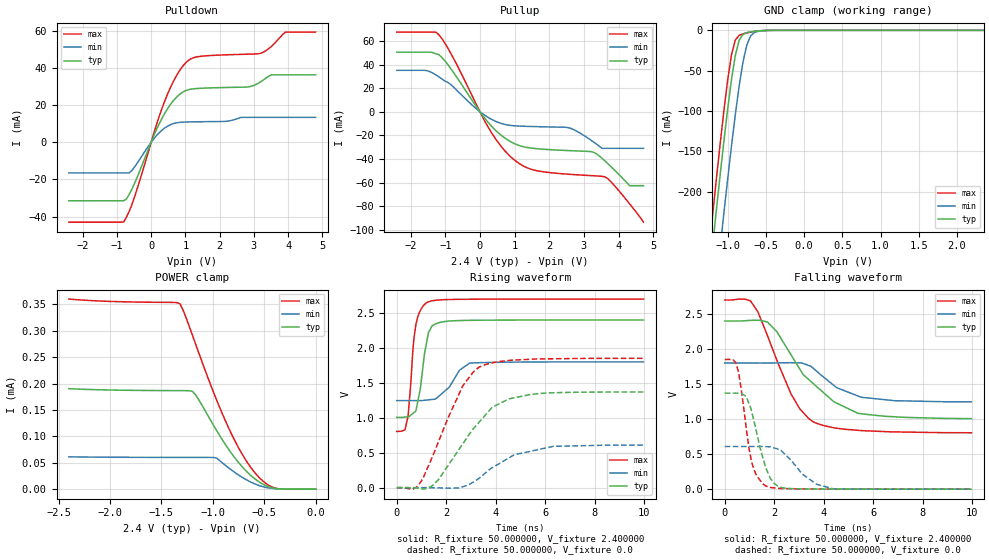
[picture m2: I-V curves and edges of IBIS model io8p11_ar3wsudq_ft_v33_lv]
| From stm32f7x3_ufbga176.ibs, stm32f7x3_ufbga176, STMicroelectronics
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|   Model io8p11_ar3wsudq_ft_v33_lv
[Model]  io8p11_ar3wsudq_ft_v33_lv
Model_type I/O
Polarity   Non-Inverting
Enable   Active-Low
Vinl =   0.720000V
Vinh =   1.680000V
Vmeas =  1.200000V
Cref =   30.000000pF
Rref =   100.000000M
Vref =   0.0V
C_comp   3.742400pF   3.690400pF   3.817400pF
[Temperature Range]   25.000000   0.125000k   -40.000000
[Pullup Reference]   2.400000V   1.800000V   2.700000V
[Pulldown Reference]   0.0V   0.0V   0.0V
[POWER Clamp Reference]   2.400000V   1.800000V   2.700000V
[GND Clamp Reference]   0.0V   0.0V   0.0V
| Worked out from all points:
|   slope of the pulldown table from 0 to 0.36 V, typ, clamps not added: 25 ohm
|   slope of the pullup table from 0 to 0.36 V, typ, clamps not added: 27.7 ohm
|   GND clamp passes 1 mA (typ) near -0.62 V on its own axis
|   rising waveform, R_fixture 50.000000, V_fixture 2.400000: 20-80 % time 350ps typ, 711ps min, 273ps max; typ from 1.01 V to 2.4 V
|   rising waveform, R_fixture 50.000000, V_fixture 0.0: 20-80 % time 1.73ns typ, 1.69ns min, 1.37ns max; typ from 0 V to 1.37 V
|   falling waveform, R_fixture 50.000000, V_fixture 2.400000: 20-80 % time 1.96ns typ, 1.49ns min, 1.39ns max; typ from 2.4 V to 1.01 V
|   falling waveform, R_fixture 50.000000, V_fixture 0.0: 20-80 % time 599ps typ, 1.04ns min, 461ps max; typ from 1.37 V to 0 V
[Pulldown]
|Voltage   I(typ)   I(min)   I(max)
-2.4V     -31.47mA   -16.45mA   -43.01mA
-800mV    -31.47mA   -16.45mA   -42.85mA
-480mV    -21.98mA   -13.17mA   -29.21mA
80mV      3.63mA     1.966mA    5.014mA
480mV     18.16mA    8.738mA    26.02mA
800mV     25.38mA    10.72mA    37.77mA
1.12V     28.53mA    11.02mA    44.6mA
2.8V      29.84mA    13.49mA    47.53mA
3.2V      32.65mA    13.49mA    48.04mA
3.52V     36.4mA     13.49mA    51.83mA
3.92V     36.4mA     13.49mA    59.44mA
4.8V      36.4mA     13.49mA    59.44mA
[Pullup]
|Voltage   I(typ)   I(min)   I(max)
-2.4V     50.45mA    35.09mA    67.46mA
-1.52V    50.45mA    34.74mA    67.46mA
-1.2V     48.61mA    29.87mA    65.61mA
-800mV    34.81mA    21.95mA    47.28mA
320mV     -11.75mA   -6.207mA   -17.08mA
1.04V     -27.54mA   -11.97mA   -41.91mA
1.6V      -31.14mA   -12.58mA   -49.63mA
2.56V     -32.88mA   -13.52mA   -52.9mA
3.28V     -34.25mA   -25.62mA   -54.18mA
3.6V      -41.44mA   -30.96mA   -55.03mA
4.32V     -62.58mA   -30.96mA   -77.98mA
4.72V     -62.58mA   -30.96mA   -93.5mA
[GND_clamp]
|Voltage   I(typ)   I(min)   I(max)
-2.4V     -1.437A    -1.518A    -1.41A
-1.25V    -315.9mA   -407.2mA   -278.2mA
-1.2V     -270.1mA   -361.3mA   -232.1mA
-1.15V    -225mA     -316mA     -186.8mA
-1.1V     -180.9mA   -271.3mA   -142.7mA
-1.05V    -138.2mA   -227.5mA   -100.5mA
-950mV    -61.14mA   -143.6mA   -30.43mA
-900mV    -31.23mA   -104.7mA   -12.14mA
-850mV    -12.49mA   -69.4mA    -6.221mA
-750mV    -2.898mA   -18.35mA   -3.18mA
-600mV    -750.2uA   -1.218mA   -738.3uA
2.35V     0A         0A         0A
[POWER_clamp]
|Voltage   I(typ)   I(min)   I(max)
-2.4V     190.2uA    61.19uA    359.9uA
-1.32V    186.6uA    60.14uA    351.2uA
-1.29V    186.5uA    60.13uA    339.6uA
-1.2V     185.4uA    60.11uA    292.6uA
-1.17V    179.2uA    60.11uA    276.3uA
-960mV    110.2uA    58.62uA    167.5uA
-870mV    82.44uA    43.99uA    126.3uA
-750mV    50.58uA    26.92uA    78.64uA
-630mV    25.94uA    13.41uA    41.02uA
-510mV    9.22uA     4.527uA    14.97uA
-420mV    2.425uA    1.38uA     3.75uA
0V        0A         0A         0A
[Ramp]
| variable   typ   min   max
dV/dt_r  0.82164/1.72879n   0.36981/1.76846n   1.11132/1.36626n
dV/dt_f  0.83208/1.95881n   0.33222/1.49500n   1.13594/1.38984n
R_load = 50.000000
[Rising Waveform]
R_fixture= 50.000000
V_fixture= 2.400000
V_fixture_min= 1.800000
V_fixture_max= 2.700000
|time   V(typ)   V(min)   V(max)
0s        1.006V     1.247V     804.9mV
320.3ps   1.01V      1.247V     824.5mV
460.5ps   1.016V     1.247V     1.037V
660.7ps   1.065V     1.247V     2.01V
760.8ps   1.094V     1.247V     2.307V
961ps     1.44V      1.246V     2.541V
1.221ns   2.109V     1.255V     2.65V
1.562ns   2.343V     1.268V     2.682V
2.943ns   2.395V     1.783V     2.697V
9.97ns    2.4V       1.8V       2.7V
[Rising Waveform]
R_fixture= 50.000000
V_fixture= 0.0
V_fixture_min= 0.0
V_fixture_max= 0.0
|time   V(typ)   V(min)   V(max)
0s        77.96uV    35.29uV    223.3uV
860.9ps   -10.31mV   60.71uV    27.03mV
1.261ns   -5.238mV   -407.8uV   297.9mV
1.682ns   113.2mV    -2.538mV   655mV
2.663ns   624.7mV    12.35mV    1.454V
3.323ns   935.8mV    133.7mV    1.725V
3.864ns   1.151V     286.5mV    1.788V
5.405ns   1.334V     521mV      1.838V
6.326ns   1.358V     591.7mV    1.845V
9.97ns    1.37V      609.1mV    1.851V
[Falling Waveform]
R_fixture= 50.000000
V_fixture= 2.400000
V_fixture_min= 1.800000
V_fixture_max= 2.700000
|time   V(typ)   V(min)   V(max)
0s        2.4V       1.8V       2.7V
1.041ns   2.409V     1.8V       2.687V
1.321ns   2.41V      1.8V       2.544V
1.722ns   2.387V     1.8V       2.197V
2.683ns   1.916V     1.805V     1.358V
3.183ns   1.63V      1.792V     1.089V
3.604ns   1.499V     1.718V     956.1mV
4.525ns   1.228V     1.449V     870mV
5.385ns   1.083V     1.33V      839.8mV
9.97ns    1.006V     1.247V     804.9mV
[Falling Waveform]
R_fixture= 50.000000
V_fixture= 0.0
V_fixture_min= 0.0
V_fixture_max= 0.0
|time   V(typ)   V(min)   V(max)
0s        1.37V      609.1mV    1.851V
460.5ps   1.371V     609mV      1.795V
660.7ps   1.366V     608.9mV    1.446V
860.9ps   1.327V     608.9mV    895.8mV
1.181ns   974.4mV    608.7mV    278.6mV
1.682ns   285.8mV    606.8mV    42.83mV
2.262ns   26.51mV    558mV      9.868mV
3.143ns   3.921mV    214.4mV    3.331mV
4.364ns   1.491mV    6.448mV    1.217mV
9.97ns    77.96uV    35.29uV    223.3uV
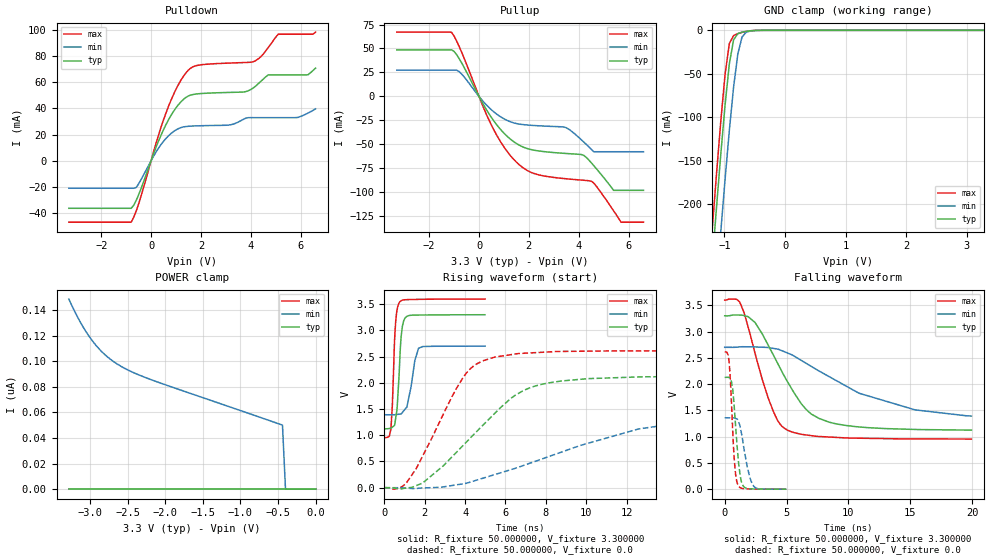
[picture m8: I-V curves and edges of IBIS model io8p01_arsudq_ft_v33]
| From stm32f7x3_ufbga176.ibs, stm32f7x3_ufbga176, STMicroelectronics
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|   Model io8p01_arsudq_ft_v33
[Model]  io8p01_arsudq_ft_v33
Model_type I/O
Polarity   Non-Inverting
Enable   Active-Low
Vinl =   0.990000V
Vinh =   2.310000V
Vmeas =  1.650000V
Cref =   50.000000pF
Rref =   100.000000M
Vref =   0.0V
C_comp   2.292100pF   2.219400pF   2.369900pF
[Temperature Range]   25.000000   0.125000k   -40.000000
[Pullup Reference]   3.300000V   2.700000V   3.600000V
[Pulldown Reference]   0.0V   0.0V   0.0V
[POWER Clamp Reference]   3.300000V   2.700000V   3.600000V
[GND Clamp Reference]   0.0V   0.0V   0.0V
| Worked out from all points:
|   slope of the pulldown table from 0 to 0.495 V, typ, clamps not added: 20.9 ohm
|   slope of the pullup table from 0 to 0.495 V, typ, clamps not added: 22.6 ohm
|   GND clamp passes 1 mA (typ) near -0.62 V on its own axis
|   rising waveform, R_fixture 50.000000, V_fixture 3.300000: 20-80 % time 191ps typ, 345ps min, 162ps max; typ from 1.12 V to 3.3 V
|   rising waveform, R_fixture 50.000000, V_fixture 0.0: 20-80 % time 3.33ns typ, 6.63ns min, 2.1ns max; typ from 0 V to 2.13 V
|   falling waveform, R_fixture 50.000000, V_fixture 3.300000: 20-80 % time 3.19ns typ, 7.05ns min, 2.02ns max; typ from 3.3 V to 1.12 V
|   falling waveform, R_fixture 50.000000, V_fixture 0.0: 20-80 % time 435ps typ, 651ps min, 337ps max; typ from 2.13 V to 0 V
[Pulldown]
|Voltage   I(typ)   I(min)   I(max)
-3.3V     -36.46mA   -21.09mA   -47.09mA
-800mV    -36.46mA   -21.09mA   -47.09mA
-600mV    -30.5mA    -20.54mA   -38.69mA
700mV     31.4mA     19.11mA    41.71mA
1.2V      45.15mA    25.37mA    61.75mA
1.6V      50.35mA    26.5mA     71.06mA
3.1V      52.28mA    27.26mA    74.76mA
4.1V      55.7mA     32.97mA    75.81mA
4.7V      65.71mA    32.97mA    86.64mA
5.1V      65.71mA    32.97mA    96.9mA
6.3V      65.88mA    36.51mA    96.9mA
6.6V      70.94mA    39.72mA    98.51mA
[Pullup]
|Voltage   I(typ)   I(min)   I(max)
-3.3V     48.51mA    27.42mA    67.12mA
-1.1V     48.51mA    27.42mA    66.85mA
-700mV    35.13mA    23.47mA    46.35mA
500mV     -22.07mA   -14mA      -30.03mA
1.5V      -49.1mA    -28.3mA    -68.56mA
2.2V      -56.05mA   -30.32mA   -80.35mA
3.5V      -59.53mA   -32.65mA   -85.92mA
4.2V      -61.43mA   -47.47mA   -87.46mA
4.5V      -69.06mA   -55.01mA   -88.38mA
5.4V      -98mA      -57.7mA    -119.3mA
5.7V      -98mA      -57.7mA    -131.2mA
6.6V      -98mA      -57.7mA    -131.2mA
[GND_clamp]
|Voltage   I(typ)   I(min)   I(max)
-3.3V     -2.314A    -2.394A    -2.288A
-1.2V     -265.5mA   -356.1mA   -227.2mA
-1.13V    -202.6mA   -292.9mA   -164.1mA
-1.06V    -142.2mA   -231.2mA   -104.1mA
-990mV    -85.98mA   -171.6mA   -50.72mA
-920mV    -38.8mA    -115.5mA   -15.28mA
-850mV    -11.08mA   -65.6mA    -6.001mA
-780mV    -3.782mA   -27.42mA   -3.876mA
-710mV    -2.086mA   -7.69mA    -2.381mA
-640mV    -1.147mA   -2.118mA   -1.22mA
-570mV    -523.9uA   -798.4uA   -476.8uA
3.28V     0A         0A         0A
[POWER_clamp]
|Voltage   I(typ)   I(min)   I(max)
-3.28V    0A         148.5nA    0A
-3.2V     0A         138.6nA    0A
-3.12V    0A         129.7nA    0A
-3.04V    0A         122nA      0A
-2.96V    0A         115.3nA    0A
-2.8V     0A         105.1nA    0A
-2.6V     0A         96.44nA    0A
-2.4V     0A         90.52nA    0A
-2.16V    0A         84.97nA    0A
-440mV    0A         50.04nA    0A
-400mV    0A         0A         0A
0V        0A         0A         0A
[Ramp]
| variable   typ   min   max
dV/dt_r  1.27764/3.32486n   0.80094/6.65667n   1.56774/2.09531n
dV/dt_f  1.30266/3.19579n   0.74364/7.03715n   1.58790/2.01979n
R_load = 50.000000
[Rising Waveform]
R_fixture= 50.000000
V_fixture= 3.300000
V_fixture_min= 2.700000
V_fixture_max= 3.600000
|time   V(typ)   V(min)   V(max)
0s        1.124V     1.392V     954.2mV
320.3ps   1.133V     1.392V     1.121V
550.6ps   1.308V     1.394V     3.13V
630.6ps   1.533V     1.398V     3.401V
750.8ps   2.358V     1.403V     3.54V
830.8ps   2.891V     1.41V      3.568V
961ps     3.191V     1.469V     3.584V
1.111ns   3.268V     1.538V     3.588V
1.692ns   3.294V     2.659V     3.593V
4.985ns   3.3V       2.7V       3.599V
[Rising Waveform]
R_fixture= 50.000000
V_fixture= 0.0
V_fixture_min= 0.0
V_fixture_max= 0.0
|time   V(typ)   V(min)   V(max)
0s        195.4uV    84.51uV    747.5uV
1.081ns   -6.558mV   -5.321mV   86.62mV
1.922ns   98.61mV    -3.136mV   625.6mV
3.844ns   784.4mV    70.95mV    2.068V
4.885ns   1.193V     181.6mV    2.421V
6.486ns   1.764V     370.2mV    2.551V
8.128ns   1.999V     591.8mV    2.59V
12.61ns   2.113V     1.122V     2.611V
15.54ns   2.122V     1.283V     2.611V
19.94ns   2.129V     1.359V     2.612V
[Falling Waveform]
R_fixture= 50.000000
V_fixture= 3.300000
V_fixture_min= 2.700000
V_fixture_max= 3.600000
|time   V(typ)   V(min)   V(max)
0s        3.3V       2.7V       3.599V
1.201ns   3.314V     2.708V     3.567V
2.442ns   3.175V     2.707V     2.595V
3.524ns   2.737V     2.695V     1.728V
4.284ns   2.393V     2.666V     1.304V
5.005ns   2.072V     2.599V     1.133V
6.567ns   1.521V     2.398V     1.032V
8.448ns   1.275V     2.141V     992.5mV
15.38ns   1.137V     1.51V      956.7mV
19.94ns   1.124V     1.392V     954.2mV
[Falling Waveform]
R_fixture= 50.000000
V_fixture= 0.0
V_fixture_min= 0.0
V_fixture_max= 0.0
|time   V(typ)   V(min)   V(max)
0s        2.129V     1.359V     2.612V
340.3ps   2.125V     1.358V     2.458V
550.6ps   2.045V     1.358V     1.624V
810.8ps   1.439V     1.353V     457.5mV
1.071ns   637.1mV    1.306V     83.4mV
1.251ns   259.8mV    1.185V     29.27mV
1.431ns   88.51mV    962.9mV    14.38mV
1.822ns   12.67mV    426.4mV    6.022mV
2.332ns   3.588mV    60.26mV    3.121mV
4.985ns   195.4uV    84.51uV    747.5uV
